VERSION 5.7 ;
BUSBITCHARS "[]" ;
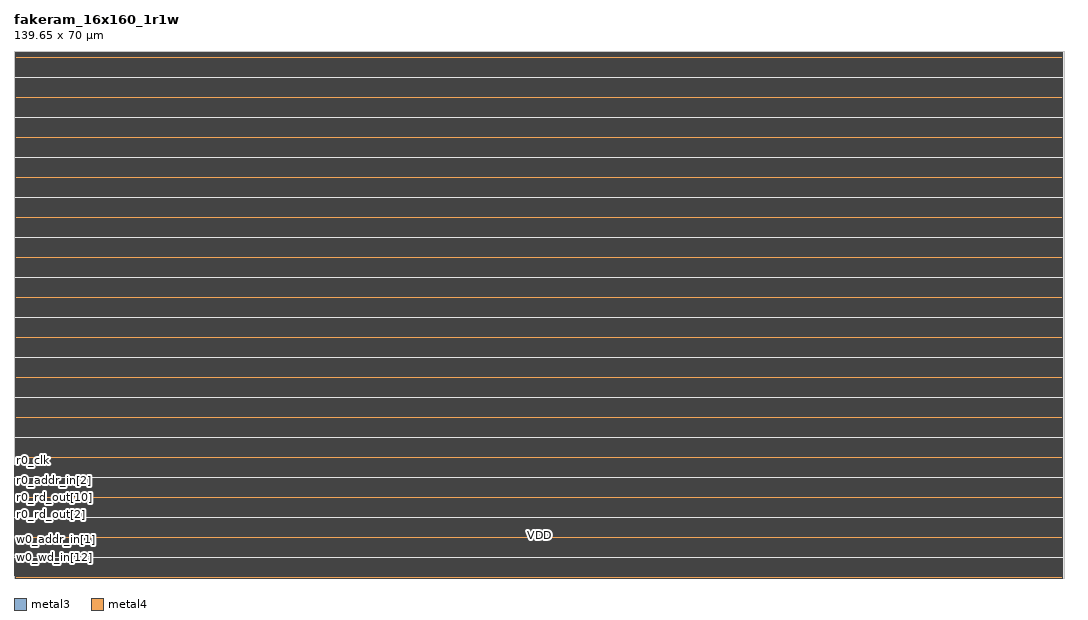
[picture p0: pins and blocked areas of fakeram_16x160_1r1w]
MACRO fakeram_16x160_1r1w
  FOREIGN fakeram_16x160_1r1w 0 0 ;
  SYMMETRY X Y R90 ;
  SIZE 139.650 BY 70.000 ;
  CLASS BLOCK ;
  PIN w0_wd_in[0]
    DIRECTION INPUT ;
    USE SIGNAL ;
    SHAPE ABUTMENT ;
    PORT
      LAYER metal3 ;
      RECT 0.000 0.280 0.140 0.420 ;
    END
  END w0_wd_in[0]
  PIN w0_wd_in[1]
    DIRECTION INPUT ;
    USE SIGNAL ;
    SHAPE ABUTMENT ;
    PORT
      LAYER metal3 ;
      RECT 0.000 0.560 0.140 0.700 ;
    END
  END w0_wd_in[1]
  PIN w0_wd_in[2]
    DIRECTION INPUT ;
    USE SIGNAL ;
    SHAPE ABUTMENT ;
    PORT
      LAYER metal3 ;
      RECT 0.000 0.840 0.140 0.980 ;
    END
  END w0_wd_in[2]
  PIN w0_wd_in[3]
    DIRECTION INPUT ;
    USE SIGNAL ;
    SHAPE ABUTMENT ;
    PORT
      LAYER metal3 ;
      RECT 0.000 1.120 0.140 1.260 ;
    END
  END w0_wd_in[3]
  PIN w0_wd_in[4]
    DIRECTION INPUT ;
    USE SIGNAL ;
    SHAPE ABUTMENT ;
    PORT
      LAYER metal3 ;
      RECT 0.000 1.400 0.140 1.540 ;
    END
  END w0_wd_in[4]
  PIN w0_wd_in[5]
    DIRECTION INPUT ;
    USE SIGNAL ;
    SHAPE ABUTMENT ;
    PORT
      LAYER metal3 ;
      RECT 0.000 1.680 0.140 1.820 ;
    END
  END w0_wd_in[5]
  PIN w0_wd_in[6]
    DIRECTION INPUT ;
    USE SIGNAL ;
    SHAPE ABUTMENT ;
    PORT
      LAYER metal3 ;
      RECT 0.000 1.960 0.140 2.100 ;
    END
  END w0_wd_in[6]
  PIN w0_wd_in[7]
    DIRECTION INPUT ;
    USE SIGNAL ;
    SHAPE ABUTMENT ;
    PORT
      LAYER metal3 ;
      RECT 0.000 2.240 0.140 2.380 ;
    END
  END w0_wd_in[7]
  PIN w0_wd_in[8]
    DIRECTION INPUT ;
    USE SIGNAL ;
    SHAPE ABUTMENT ;
    PORT
      LAYER metal3 ;
      RECT 0.000 2.520 0.140 2.660 ;
    END
  END w0_wd_in[8]
  PIN w0_wd_in[9]
    DIRECTION INPUT ;
    USE SIGNAL ;
    SHAPE ABUTMENT ;
    PORT
      LAYER metal3 ;
      RECT 0.000 2.800 0.140 2.940 ;
    END
  END w0_wd_in[9]
  PIN w0_wd_in[10]
    DIRECTION INPUT ;
    USE SIGNAL ;
    SHAPE ABUTMENT ;
    PORT
      LAYER metal3 ;
      RECT 0.000 3.080 0.140 3.220 ;
    END
  END w0_wd_in[10]
  PIN w0_wd_in[11]
    DIRECTION INPUT ;
    USE SIGNAL ;
    SHAPE ABUTMENT ;
    PORT
      LAYER metal3 ;
      RECT 0.000 3.360 0.140 3.500 ;
    END
  END w0_wd_in[11]
  PIN w0_wd_in[12]
    DIRECTION INPUT ;
    USE SIGNAL ;
    SHAPE ABUTMENT ;
    PORT
      LAYER metal3 ;
      RECT 0.000 3.640 0.140 3.780 ;
    END
  END w0_wd_in[12]
  PIN w0_wd_in[13]
    DIRECTION INPUT ;
    USE SIGNAL ;
    SHAPE ABUTMENT ;
    PORT
      LAYER metal3 ;
      RECT 0.000 3.920 0.140 4.060 ;
    END
  END w0_wd_in[13]
  PIN w0_wd_in[14]
    DIRECTION INPUT ;
    USE SIGNAL ;
    SHAPE ABUTMENT ;
    PORT
      LAYER metal3 ;
      RECT 0.000 4.200 0.140 4.340 ;
    END
  END w0_wd_in[14]
  PIN w0_wd_in[15]
    DIRECTION INPUT ;
    USE SIGNAL ;
    SHAPE ABUTMENT ;
    PORT
      LAYER metal3 ;
      RECT 0.000 4.480 0.140 4.620 ;
    END
  END w0_wd_in[15]
  PIN w0_addr_in[0]
    DIRECTION INPUT ;
    USE SIGNAL ;
    SHAPE ABUTMENT ;
    PORT
      LAYER metal3 ;
      RECT 0.000 4.760 0.140 4.900 ;
    END
  END w0_addr_in[0]
  PIN w0_addr_in[1]
    DIRECTION INPUT ;
    USE SIGNAL ;
    SHAPE ABUTMENT ;
    PORT
      LAYER metal3 ;
      RECT 0.000 5.040 0.140 5.180 ;
    END
  END w0_addr_in[1]
  PIN w0_addr_in[2]
    DIRECTION INPUT ;
    USE SIGNAL ;
    SHAPE ABUTMENT ;
    PORT
      LAYER metal3 ;
      RECT 0.000 5.320 0.140 5.460 ;
    END
  END w0_addr_in[2]
  PIN w0_addr_in[3]
    DIRECTION INPUT ;
    USE SIGNAL ;
    SHAPE ABUTMENT ;
    PORT
      LAYER metal3 ;
      RECT 0.000 5.600 0.140 5.740 ;
    END
  END w0_addr_in[3]
  PIN w0_addr_in[4]
    DIRECTION INPUT ;
    USE SIGNAL ;
    SHAPE ABUTMENT ;
    PORT
      LAYER metal3 ;
      RECT 0.000 5.880 0.140 6.020 ;
    END
  END w0_addr_in[4]
  PIN w0_addr_in[5]
    DIRECTION INPUT ;
    USE SIGNAL ;
    SHAPE ABUTMENT ;
    PORT
      LAYER metal3 ;
      RECT 0.000 6.160 0.140 6.300 ;
    END
  END w0_addr_in[5]
  PIN w0_addr_in[6]
    DIRECTION INPUT ;
    USE SIGNAL ;
    SHAPE ABUTMENT ;
    PORT
      LAYER metal3 ;
      RECT 0.000 6.440 0.140 6.580 ;
    END
  END w0_addr_in[6]
  PIN w0_addr_in[7]
    DIRECTION INPUT ;
    USE SIGNAL ;
    SHAPE ABUTMENT ;
    PORT
      LAYER metal3 ;
      RECT 0.000 6.720 0.140 6.860 ;
    END
  END w0_addr_in[7]
  PIN w0_clk
    DIRECTION INPUT ;
    USE SIGNAL ;
    SHAPE ABUTMENT ;
    PORT
      LAYER metal3 ;
      RECT 0.000 7.000 0.140 7.140 ;
    END
  END w0_clk
  PIN w0_ce_in
    DIRECTION INPUT ;
    USE SIGNAL ;
    SHAPE ABUTMENT ;
    PORT
      LAYER metal3 ;
      RECT 0.000 7.280 0.140 7.420 ;
    END
  END w0_ce_in
  PIN w0_we_in
    DIRECTION INPUT ;
    USE SIGNAL ;
    SHAPE ABUTMENT ;
    PORT
      LAYER metal3 ;
      RECT 0.000 7.560 0.140 7.700 ;
    END
  END w0_we_in
  PIN r0_rd_out[0]
    DIRECTION OUTPUT ;
    USE SIGNAL ;
    SHAPE ABUTMENT ;
    PORT
      LAYER metal3 ;
      RECT 0.000 7.840 0.140 7.980 ;
    END
  END r0_rd_out[0]
  PIN r0_rd_out[1]
    DIRECTION OUTPUT ;
    USE SIGNAL ;
    SHAPE ABUTMENT ;
    PORT
      LAYER metal3 ;
      RECT 0.000 8.120 0.140 8.260 ;
    END
  END r0_rd_out[1]
  PIN r0_rd_out[2]
    DIRECTION OUTPUT ;
    USE SIGNAL ;
    SHAPE ABUTMENT ;
    PORT
      LAYER metal3 ;
      RECT 0.000 8.400 0.140 8.540 ;
    END
  END r0_rd_out[2]
  PIN r0_rd_out[3]
    DIRECTION OUTPUT ;
    USE SIGNAL ;
    SHAPE ABUTMENT ;
    PORT
      LAYER metal3 ;
      RECT 0.000 8.680 0.140 8.820 ;
    END
  END r0_rd_out[3]
  PIN r0_rd_out[4]
    DIRECTION OUTPUT ;
    USE SIGNAL ;
    SHAPE ABUTMENT ;
    PORT
      LAYER metal3 ;
      RECT 0.000 8.960 0.140 9.100 ;
    END
  END r0_rd_out[4]
  PIN r0_rd_out[5]
    DIRECTION OUTPUT ;
    USE SIGNAL ;
    SHAPE ABUTMENT ;
    PORT
      LAYER metal3 ;
      RECT 0.000 9.240 0.140 9.380 ;
    END
  END r0_rd_out[5]
  PIN r0_rd_out[6]
    DIRECTION OUTPUT ;
    USE SIGNAL ;
    SHAPE ABUTMENT ;
    PORT
      LAYER metal3 ;
      RECT 0.000 9.520 0.140 9.660 ;
    END
  END r0_rd_out[6]
  PIN r0_rd_out[7]
    DIRECTION OUTPUT ;
    USE SIGNAL ;
    SHAPE ABUTMENT ;
    PORT
      LAYER metal3 ;
      RECT 0.000 9.800 0.140 9.940 ;
    END
  END r0_rd_out[7]
  PIN r0_rd_out[8]
    DIRECTION OUTPUT ;
    USE SIGNAL ;
    SHAPE ABUTMENT ;
    PORT
      LAYER metal3 ;
      RECT 0.000 10.080 0.140 10.220 ;
    END
  END r0_rd_out[8]
  PIN r0_rd_out[9]
    DIRECTION OUTPUT ;
    USE SIGNAL ;
    SHAPE ABUTMENT ;
    PORT
      LAYER metal3 ;
      RECT 0.000 10.360 0.140 10.500 ;
    END
  END r0_rd_out[9]
  PIN r0_rd_out[10]
    DIRECTION OUTPUT ;
    USE SIGNAL ;
    SHAPE ABUTMENT ;
    PORT
      LAYER metal3 ;
      RECT 0.000 10.640 0.140 10.780 ;
    END
  END r0_rd_out[10]
  PIN r0_rd_out[11]
    DIRECTION OUTPUT ;
    USE SIGNAL ;
    SHAPE ABUTMENT ;
    PORT
      LAYER metal3 ;
      RECT 0.000 10.920 0.140 11.060 ;
    END
  END r0_rd_out[11]
  PIN r0_rd_out[12]
    DIRECTION OUTPUT ;
    USE SIGNAL ;
    SHAPE ABUTMENT ;
    PORT
      LAYER metal3 ;
      RECT 0.000 11.200 0.140 11.340 ;
    END
  END r0_rd_out[12]
  PIN r0_rd_out[13]
    DIRECTION OUTPUT ;
    USE SIGNAL ;
    SHAPE ABUTMENT ;
    PORT
      LAYER metal3 ;
      RECT 0.000 11.480 0.140 11.620 ;
    END
  END r0_rd_out[13]
  PIN r0_rd_out[14]
    DIRECTION OUTPUT ;
    USE SIGNAL ;
    SHAPE ABUTMENT ;
    PORT
      LAYER metal3 ;
      RECT 0.000 11.760 0.140 11.900 ;
    END
  END r0_rd_out[14]
  PIN r0_rd_out[15]
    DIRECTION OUTPUT ;
    USE SIGNAL ;
    SHAPE ABUTMENT ;
    PORT
      LAYER metal3 ;
      RECT 0.000 12.040 0.140 12.180 ;
    END
  END r0_rd_out[15]
  PIN r0_addr_in[0]
    DIRECTION INPUT ;
    USE SIGNAL ;
    SHAPE ABUTMENT ;
    PORT
      LAYER metal3 ;
      RECT 0.000 12.320 0.140 12.460 ;
    END
  END r0_addr_in[0]
  PIN r0_addr_in[1]
    DIRECTION INPUT ;
    USE SIGNAL ;
    SHAPE ABUTMENT ;
    PORT
      LAYER metal3 ;
      RECT 0.000 12.600 0.140 12.740 ;
    END
  END r0_addr_in[1]
  PIN r0_addr_in[2]
    DIRECTION INPUT ;
    USE SIGNAL ;
    SHAPE ABUTMENT ;
    PORT
      LAYER metal3 ;
      RECT 0.000 12.880 0.140 13.020 ;
    END
  END r0_addr_in[2]
  PIN r0_addr_in[3]
    DIRECTION INPUT ;
    USE SIGNAL ;
    SHAPE ABUTMENT ;
    PORT
      LAYER metal3 ;
      RECT 0.000 13.160 0.140 13.300 ;
    END
  END r0_addr_in[3]
  PIN r0_addr_in[4]
    DIRECTION INPUT ;
    USE SIGNAL ;
    SHAPE ABUTMENT ;
    PORT
      LAYER metal3 ;
      RECT 0.000 13.440 0.140 13.580 ;
    END
  END r0_addr_in[4]
  PIN r0_addr_in[5]
    DIRECTION INPUT ;
    USE SIGNAL ;
    SHAPE ABUTMENT ;
    PORT
      LAYER metal3 ;
      RECT 0.000 13.720 0.140 13.860 ;
    END
  END r0_addr_in[5]
  PIN r0_addr_in[6]
    DIRECTION INPUT ;
    USE SIGNAL ;
    SHAPE ABUTMENT ;
    PORT
      LAYER metal3 ;
      RECT 0.000 14.000 0.140 14.140 ;
    END
  END r0_addr_in[6]
  PIN r0_addr_in[7]
    DIRECTION INPUT ;
    USE SIGNAL ;
    SHAPE ABUTMENT ;
    PORT
      LAYER metal3 ;
      RECT 0.000 14.280 0.140 14.420 ;
    END
  END r0_addr_in[7]
  PIN r0_clk
    DIRECTION INPUT ;
    USE SIGNAL ;
    SHAPE ABUTMENT ;
    PORT
      LAYER metal3 ;
      RECT 0.000 14.560 0.140 14.700 ;
    END
  END r0_clk
  PIN r0_ce_in
    DIRECTION INPUT ;
    USE SIGNAL ;
    SHAPE ABUTMENT ;
    PORT
      LAYER metal3 ;
      RECT 0.000 14.840 0.140 14.980 ;
    END
  END r0_ce_in
  PIN VDD
    DIRECTION INOUT ;
    USE POWER ;
    PORT
      LAYER metal4 ;
      RECT 0.190 0.000 139.460 0.140 ;
      RECT 0.190 0.560 139.460 0.700 ;
      RECT 0.190 1.120 139.460 1.260 ;
      RECT 0.190 1.680 139.460 1.820 ;
      RECT 0.190 2.240 139.460 2.380 ;
      RECT 0.190 2.800 139.460 2.940 ;
      RECT 0.190 3.360 139.460 3.500 ;
      RECT 0.190 3.920 139.460 4.060 ;
      RECT 0.190 4.480 139.460 4.620 ;
      RECT 0.190 5.040 139.460 5.180 ;
      RECT 0.190 5.600 139.460 5.740 ;
      RECT 0.190 6.160 139.460 6.300 ;
      RECT 0.190 6.720 139.460 6.860 ;
      RECT 0.190 7.280 139.460 7.420 ;
      RECT 0.190 7.840 139.460 7.980 ;
      RECT 0.190 8.400 139.460 8.540 ;
      RECT 0.190 8.960 139.460 9.100 ;
      RECT 0.190 9.520 139.460 9.660 ;
      RECT 0.190 10.080 139.460 10.220 ;
      RECT 0.190 10.640 139.460 10.780 ;
      RECT 0.190 11.200 139.460 11.340 ;
      RECT 0.190 11.760 139.460 11.900 ;
      RECT 0.190 12.320 139.460 12.460 ;
      RECT 0.190 12.880 139.460 13.020 ;
      RECT 0.190 13.440 139.460 13.580 ;
      RECT 0.190 14.000 139.460 14.140 ;
      RECT 0.190 14.560 139.460 14.700 ;
      RECT 0.190 15.120 139.460 15.260 ;
      RECT 0.190 15.680 139.460 15.820 ;
      RECT 0.190 16.240 139.460 16.380 ;
      RECT 0.190 16.800 139.460 16.940 ;
      RECT 0.190 17.360 139.460 17.500 ;
      RECT 0.190 17.920 139.460 18.060 ;
      RECT 0.190 18.480 139.460 18.620 ;
      RECT 0.190 19.040 139.460 19.180 ;
      RECT 0.190 19.600 139.460 19.740 ;
      RECT 0.190 20.160 139.460 20.300 ;
      RECT 0.190 20.720 139.460 20.860 ;
      RECT 0.190 21.280 139.460 21.420 ;
      RECT 0.190 21.840 139.460 21.980 ;
      RECT 0.190 22.400 139.460 22.540 ;
      RECT 0.190 22.960 139.460 23.100 ;
      RECT 0.190 23.520 139.460 23.660 ;
      RECT 0.190 24.080 139.460 24.220 ;
      RECT 0.190 24.640 139.460 24.780 ;
      RECT 0.190 25.200 139.460 25.340 ;
      RECT 0.190 25.760 139.460 25.900 ;
      RECT 0.190 26.320 139.460 26.460 ;
      RECT 0.190 26.880 139.460 27.020 ;
      RECT 0.190 27.440 139.460 27.580 ;
      RECT 0.190 28.000 139.460 28.140 ;
      RECT 0.190 28.560 139.460 28.700 ;
      RECT 0.190 29.120 139.460 29.260 ;
      RECT 0.190 29.680 139.460 29.820 ;
      RECT 0.190 30.240 139.460 30.380 ;
      RECT 0.190 30.800 139.460 30.940 ;
      RECT 0.190 31.360 139.460 31.500 ;
      RECT 0.190 31.920 139.460 32.060 ;
      RECT 0.190 32.480 139.460 32.620 ;
      RECT 0.190 33.040 139.460 33.180 ;
      RECT 0.190 33.600 139.460 33.740 ;
      RECT 0.190 34.160 139.460 34.300 ;
      RECT 0.190 34.720 139.460 34.860 ;
      RECT 0.190 35.280 139.460 35.420 ;
      RECT 0.190 35.840 139.460 35.980 ;
      RECT 0.190 36.400 139.460 36.540 ;
      RECT 0.190 36.960 139.460 37.100 ;
      RECT 0.190 37.520 139.460 37.660 ;
      RECT 0.190 38.080 139.460 38.220 ;
      RECT 0.190 38.640 139.460 38.780 ;
      RECT 0.190 39.200 139.460 39.340 ;
      RECT 0.190 39.760 139.460 39.900 ;
      RECT 0.190 40.320 139.460 40.460 ;
      RECT 0.190 40.880 139.460 41.020 ;
      RECT 0.190 41.440 139.460 41.580 ;
      RECT 0.190 42.000 139.460 42.140 ;
      RECT 0.190 42.560 139.460 42.700 ;
      RECT 0.190 43.120 139.460 43.260 ;
      RECT 0.190 43.680 139.460 43.820 ;
      RECT 0.190 44.240 139.460 44.380 ;
      RECT 0.190 44.800 139.460 44.940 ;
      RECT 0.190 45.360 139.460 45.500 ;
      RECT 0.190 45.920 139.460 46.060 ;
      RECT 0.190 46.480 139.460 46.620 ;
      RECT 0.190 47.040 139.460 47.180 ;
      RECT 0.190 47.600 139.460 47.740 ;
      RECT 0.190 48.160 139.460 48.300 ;
      RECT 0.190 48.720 139.460 48.860 ;
      RECT 0.190 49.280 139.460 49.420 ;
      RECT 0.190 49.840 139.460 49.980 ;
      RECT 0.190 50.400 139.460 50.540 ;
      RECT 0.190 50.960 139.460 51.100 ;
      RECT 0.190 51.520 139.460 51.660 ;
      RECT 0.190 52.080 139.460 52.220 ;
      RECT 0.190 52.640 139.460 52.780 ;
      RECT 0.190 53.200 139.460 53.340 ;
      RECT 0.190 53.760 139.460 53.900 ;
      RECT 0.190 54.320 139.460 54.460 ;
      RECT 0.190 54.880 139.460 55.020 ;
      RECT 0.190 55.440 139.460 55.580 ;
      RECT 0.190 56.000 139.460 56.140 ;
      RECT 0.190 56.560 139.460 56.700 ;
      RECT 0.190 57.120 139.460 57.260 ;
      RECT 0.190 57.680 139.460 57.820 ;
      RECT 0.190 58.240 139.460 58.380 ;
      RECT 0.190 58.800 139.460 58.940 ;
      RECT 0.190 59.360 139.460 59.500 ;
      RECT 0.190 59.920 139.460 60.060 ;
      RECT 0.190 60.480 139.460 60.620 ;
      RECT 0.190 61.040 139.460 61.180 ;
      RECT 0.190 61.600 139.460 61.740 ;
      RECT 0.190 62.160 139.460 62.300 ;
      RECT 0.190 62.720 139.460 62.860 ;
      RECT 0.190 63.280 139.460 63.420 ;
      RECT 0.190 63.840 139.460 63.980 ;
      RECT 0.190 64.400 139.460 64.540 ;
      RECT 0.190 64.960 139.460 65.100 ;
      RECT 0.190 65.520 139.460 65.660 ;
      RECT 0.190 66.080 139.460 66.220 ;
      RECT 0.190 66.640 139.460 66.780 ;
      RECT 0.190 67.200 139.460 67.340 ;
      RECT 0.190 67.760 139.460 67.900 ;
      RECT 0.190 68.320 139.460 68.460 ;
      RECT 0.190 68.880 139.460 69.020 ;
      RECT 0.190 69.440 139.460 69.580 ;
    END
  END VDD
  PIN VSS
    DIRECTION INOUT ;
    USE GROUND ;
    PORT
      LAYER metal4 ;
      RECT 0.190 0.280 139.460 0.420 ;
      RECT 0.190 0.840 139.460 0.980 ;
      RECT 0.190 1.400 139.460 1.540 ;
      RECT 0.190 1.960 139.460 2.100 ;
      RECT 0.190 2.520 139.460 2.660 ;
      RECT 0.190 3.080 139.460 3.220 ;
      RECT 0.190 3.640 139.460 3.780 ;
      RECT 0.190 4.200 139.460 4.340 ;
      RECT 0.190 4.760 139.460 4.900 ;
      RECT 0.190 5.320 139.460 5.460 ;
      RECT 0.190 5.880 139.460 6.020 ;
      RECT 0.190 6.440 139.460 6.580 ;
      RECT 0.190 7.000 139.460 7.140 ;
      RECT 0.190 7.560 139.460 7.700 ;
      RECT 0.190 8.120 139.460 8.260 ;
      RECT 0.190 8.680 139.460 8.820 ;
      RECT 0.190 9.240 139.460 9.380 ;
      RECT 0.190 9.800 139.460 9.940 ;
      RECT 0.190 10.360 139.460 10.500 ;
      RECT 0.190 10.920 139.460 11.060 ;
      RECT 0.190 11.480 139.460 11.620 ;
      RECT 0.190 12.040 139.460 12.180 ;
      RECT 0.190 12.600 139.460 12.740 ;
      RECT 0.190 13.160 139.460 13.300 ;
      RECT 0.190 13.720 139.460 13.860 ;
      RECT 0.190 14.280 139.460 14.420 ;
      RECT 0.190 14.840 139.460 14.980 ;
      RECT 0.190 15.400 139.460 15.540 ;
      RECT 0.190 15.960 139.460 16.100 ;
      RECT 0.190 16.520 139.460 16.660 ;
      RECT 0.190 17.080 139.460 17.220 ;
      RECT 0.190 17.640 139.460 17.780 ;
      RECT 0.190 18.200 139.460 18.340 ;
      RECT 0.190 18.760 139.460 18.900 ;
      RECT 0.190 19.320 139.460 19.460 ;
      RECT 0.190 19.880 139.460 20.020 ;
      RECT 0.190 20.440 139.460 20.580 ;
      RECT 0.190 21.000 139.460 21.140 ;
      RECT 0.190 21.560 139.460 21.700 ;
      RECT 0.190 22.120 139.460 22.260 ;
      RECT 0.190 22.680 139.460 22.820 ;
      RECT 0.190 23.240 139.460 23.380 ;
      RECT 0.190 23.800 139.460 23.940 ;
      RECT 0.190 24.360 139.460 24.500 ;
      RECT 0.190 24.920 139.460 25.060 ;
      RECT 0.190 25.480 139.460 25.620 ;
      RECT 0.190 26.040 139.460 26.180 ;
      RECT 0.190 26.600 139.460 26.740 ;
      RECT 0.190 27.160 139.460 27.300 ;
      RECT 0.190 27.720 139.460 27.860 ;
      RECT 0.190 28.280 139.460 28.420 ;
      RECT 0.190 28.840 139.460 28.980 ;
      RECT 0.190 29.400 139.460 29.540 ;
      RECT 0.190 29.960 139.460 30.100 ;
      RECT 0.190 30.520 139.460 30.660 ;
      RECT 0.190 31.080 139.460 31.220 ;
      RECT 0.190 31.640 139.460 31.780 ;
      RECT 0.190 32.200 139.460 32.340 ;
      RECT 0.190 32.760 139.460 32.900 ;
      RECT 0.190 33.320 139.460 33.460 ;
      RECT 0.190 33.880 139.460 34.020 ;
      RECT 0.190 34.440 139.460 34.580 ;
      RECT 0.190 35.000 139.460 35.140 ;
      RECT 0.190 35.560 139.460 35.700 ;
      RECT 0.190 36.120 139.460 36.260 ;
      RECT 0.190 36.680 139.460 36.820 ;
      RECT 0.190 37.240 139.460 37.380 ;
      RECT 0.190 37.800 139.460 37.940 ;
      RECT 0.190 38.360 139.460 38.500 ;
      RECT 0.190 38.920 139.460 39.060 ;
      RECT 0.190 39.480 139.460 39.620 ;
      RECT 0.190 40.040 139.460 40.180 ;
      RECT 0.190 40.600 139.460 40.740 ;
      RECT 0.190 41.160 139.460 41.300 ;
      RECT 0.190 41.720 139.460 41.860 ;
      RECT 0.190 42.280 139.460 42.420 ;
      RECT 0.190 42.840 139.460 42.980 ;
      RECT 0.190 43.400 139.460 43.540 ;
      RECT 0.190 43.960 139.460 44.100 ;
      RECT 0.190 44.520 139.460 44.660 ;
      RECT 0.190 45.080 139.460 45.220 ;
      RECT 0.190 45.640 139.460 45.780 ;
      RECT 0.190 46.200 139.460 46.340 ;
      RECT 0.190 46.760 139.460 46.900 ;
      RECT 0.190 47.320 139.460 47.460 ;
      RECT 0.190 47.880 139.460 48.020 ;
      RECT 0.190 48.440 139.460 48.580 ;
      RECT 0.190 49.000 139.460 49.140 ;
      RECT 0.190 49.560 139.460 49.700 ;
      RECT 0.190 50.120 139.460 50.260 ;
      RECT 0.190 50.680 139.460 50.820 ;
      RECT 0.190 51.240 139.460 51.380 ;
      RECT 0.190 51.800 139.460 51.940 ;
      RECT 0.190 52.360 139.460 52.500 ;
      RECT 0.190 52.920 139.460 53.060 ;
      RECT 0.190 53.480 139.460 53.620 ;
      RECT 0.190 54.040 139.460 54.180 ;
      RECT 0.190 54.600 139.460 54.740 ;
      RECT 0.190 55.160 139.460 55.300 ;
      RECT 0.190 55.720 139.460 55.860 ;
      RECT 0.190 56.280 139.460 56.420 ;
      RECT 0.190 56.840 139.460 56.980 ;
      RECT 0.190 57.400 139.460 57.540 ;
      RECT 0.190 57.960 139.460 58.100 ;
      RECT 0.190 58.520 139.460 58.660 ;
      RECT 0.190 59.080 139.460 59.220 ;
      RECT 0.190 59.640 139.460 59.780 ;
      RECT 0.190 60.200 139.460 60.340 ;
      RECT 0.190 60.760 139.460 60.900 ;
      RECT 0.190 61.320 139.460 61.460 ;
      RECT 0.190 61.880 139.460 62.020 ;
      RECT 0.190 62.440 139.460 62.580 ;
      RECT 0.190 63.000 139.460 63.140 ;
      RECT 0.190 63.560 139.460 63.700 ;
      RECT 0.190 64.120 139.460 64.260 ;
      RECT 0.190 64.680 139.460 64.820 ;
      RECT 0.190 65.240 139.460 65.380 ;
      RECT 0.190 65.800 139.460 65.940 ;
      RECT 0.190 66.360 139.460 66.500 ;
      RECT 0.190 66.920 139.460 67.060 ;
      RECT 0.190 67.480 139.460 67.620 ;
      RECT 0.190 68.040 139.460 68.180 ;
      RECT 0.190 68.600 139.460 68.740 ;
      RECT 0.190 69.160 139.460 69.300 ;
      RECT 0.190 69.720 139.460 69.860 ;
    END
  END VSS
  OBS
    LAYER metal1 ;
      RECT 0.000 0.000 139.650 70.000 ;
    LAYER metal2 ;
      RECT 0.000 0.000 139.650 70.000 ;
    LAYER metal3 ;
      RECT 0.000 0.000 139.650 70.000 ;
  END
END fakeram_16x160_1r1w
END LIBRARY
